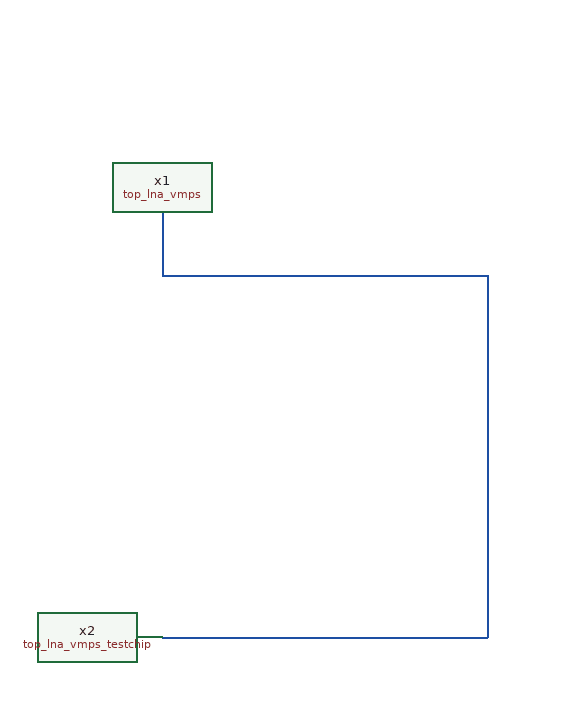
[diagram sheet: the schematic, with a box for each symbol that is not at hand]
v {xschem version=3.4.8RC file_version=1.3}
G {}
K {}
V {}
S {}
F {}
E {}
N 2610 -2450 2610 -2400 {lab=#net1}
N 2610 -2400 2870 -2400 {lab=#net1}
N 2870 -2400 2870 -2110 {lab=#net1}
N 2610 -2110 2870 -2110 {lab=#net1}
C {06_integ/top_lna_vmps.sym} 2610 -2550 0 0 {name=x1}
C {06_integ/top_lna_vmps_testchip.sym} 2610 -2210 0 0 {name=x2}
